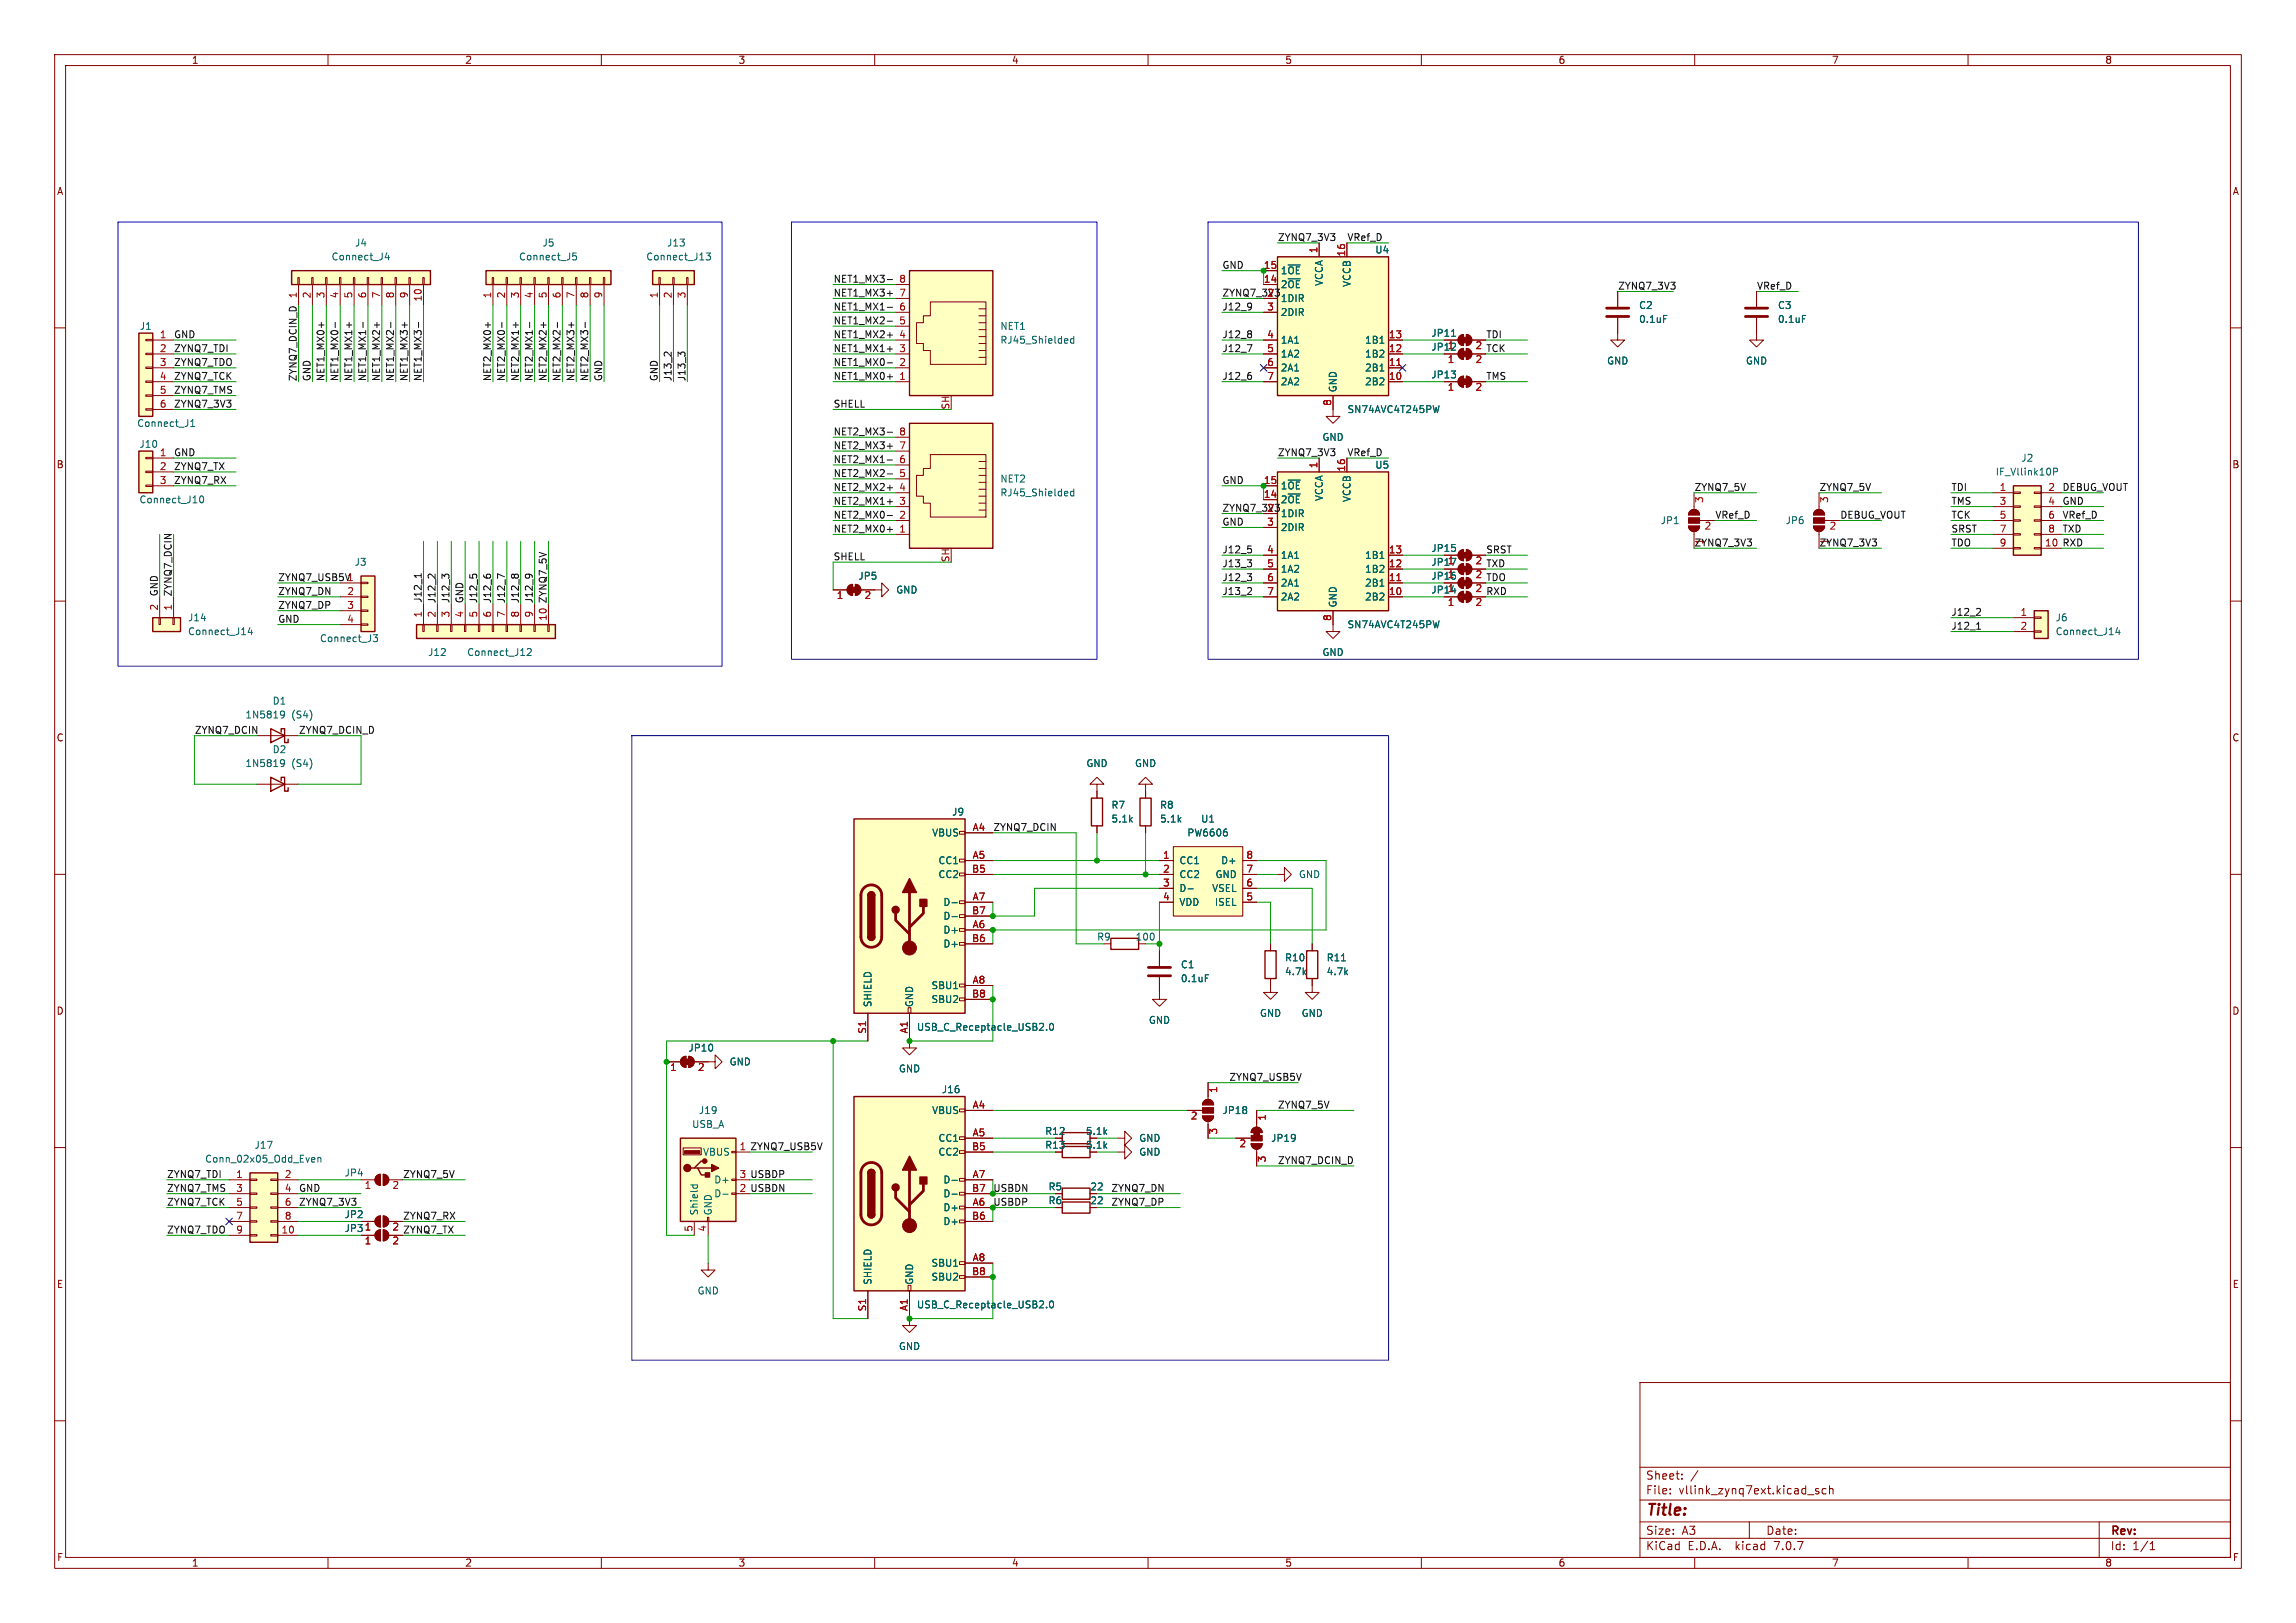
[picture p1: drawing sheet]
<svg xmlns="http://www.w3.org/2000/svg" width="420mm" height="297mm" viewBox="0 0 420 297" stroke-linecap="round" stroke-linejoin="round" font-family="sans-serif">
<defs><g id="words">
<text font-size="2.8" fill="#840000" x="301" y="277.9">Title:</text>
<g font-size="2.1" fill="#840000">
<text x="301" y="273.7">File:</text>
<text x="301" y="271">Sheet:</text>
<text x="307.1" y="273.7">vllink_zynq7ext.kicad_sch</text>
<text x="301" y="281.1">Size:</text>
<text x="307.6" y="281.1">A3</text>
<text x="323" y="281.1">Date:</text>
<text x="386" y="281.3">Rev:</text>
<text x="301" y="283.9">KiCad</text>
<text x="308.7" y="283.9">E.D.A.</text>
<text x="317.6" y="283.9">kicad</text>
<text x="324.8" y="283.9">7.0.7</text>
<text x="386" y="283.9">Id:</text>
<text x="390.1" y="283.9">1/1</text>
</g>
<g font-size="1.8" fill="#840000">
<text x="35" y="11.9">1</text>
<text x="85" y="11.9">2</text>
<text x="135" y="11.9">3</text>
<text x="185" y="11.9">4</text>
<text x="235" y="11.9">5</text>
<text x="285" y="11.9">6</text>
<text x="335" y="11.9">7</text>
<text x="385" y="11.9">8</text>
<text x="10.3" y="35.9">A</text>
<text x="408.3" y="35.9">A</text>
<text x="223.5" y="54.3">ZYNQ7_3V3</text>
<text x="269.8" y="64.2">2 TCK</text>
<text x="10.3" y="85.9">B</text>
<text x="408.2" y="85.9">B</text>
<text x="223.5" y="93.7">ZYNQ7_3V3</text>
<text x="269.8" y="106.1">2 TDO</text>
<text x="269.8" y="103.6">2 TXD</text>
<text x="269.8" y="108.7">2 RXD</text>
<text x="10.3" y="135.9">C</text>
<text x="408.2" y="135.9">C</text>
<text x="10.3" y="185.9">D</text>
<text x="408.2" y="185.9">D</text>
<text x="191.1" y="207.9">R12</text>
<text x="198.5" y="207.9">5.1k</text>
<text x="191.1" y="210.4">R13</text>
<text x="198.5" y="210.4">5.1k</text>
<text x="191.7" y="220.6">R6</text>
<text x="191.7" y="218">R5</text>
<text x="199.3" y="220.6">22</text>
<text x="199.3" y="218">22</text>
<text x="71.7" y="225.5">2 ZYNQ7_TX</text>
<text x="10.3" y="235.9">E</text>
<text x="408.3" y="235.9">E</text>
<text x="10.3" y="285.9">F</text>
<text x="35" y="286.9">1</text>
<text x="85" y="286.9">2</text>
<text x="135" y="286.9">3</text>
<text x="185" y="286.9">4</text>
<text x="235" y="286.9">5</text>
<text x="285" y="286.9">6</text>
<text x="335" y="286.9">7</text>
<text x="385" y="286.9">8</text>
<text x="408.3" y="285.9">F</text>
</g>
<g font-size="1.8" fill="#006464">
<text x="60.6" y="47.9">Connect_J4</text>
<text x="64.8" y="45.3">J4</text>
<text x="94.8" y="47.9">Connect_J5</text>
<text x="99.1" y="45.3">J5</text>
<text x="118.1" y="47.9">Connect_J13</text>
<text x="121.9" y="45.3">J13</text>
<text x="251.5" y="46.6">U4</text>
<text x="234.2" y="52.9">2~{OE}</text>
<text x="234.2" y="50.4">1~{OE}</text>
<text x="242.2" y="52.4" transform="rotate(-90 242.2 52.4)">VCCA</text>
<text x="247.2" y="52.6" transform="rotate(-90 247.2 52.6)">VCCB</text>
<text x="234.2" y="55.5">1DIR</text>
<text x="234.2" y="58">2DIR</text>
<text x="299.7" y="56.7">C2</text>
<text x="299.7" y="59.3">0.1uF</text>
<text x="325.1" y="56.7">C3</text>
<text x="325.1" y="59.3">0.1uF</text>
<text x="25.5" y="60.6">J1</text>
<text x="182.9" y="63.1">RJ45_Shielded</text>
<text x="182.9" y="60.6">NET1</text>
<text x="234.2" y="63.1">1A1</text>
<text x="234.2" y="65.6">1A2</text>
<text x="249.6" y="65.6">1B2</text>
<text x="249.6" y="63.1">1B1</text>
<text x="261.7" y="61.8">JP11</text>
<text x="261.7" y="64.4">JP12</text>
<text x="264.7" y="64.2">1</text>
<text x="234.2" y="68.2">2A1</text>
<text x="234.2" y="70.7">2A2</text>
<text x="244.7" y="71.9" transform="rotate(-90 244.7 71.9)">GND</text>
<text x="249.6" y="70.7">2B2</text>
<text x="249.6" y="68.2">2B1</text>
<text x="261.7" y="69.4">JP13</text>
<text x="293.9" y="66.9">GND</text>
<text x="319.3" y="66.9">GND</text>
<text x="246.4" y="75.8">SN74AVC4T245PW</text>
<text x="25" y="78.3">Connect_J1</text>
<text x="25.4" y="82.1">J10</text>
<text x="241.8" y="80.9">GND</text>
<text x="182.9" y="88.5">NET2</text>
<text x="234.2" y="89.8">1~{OE}</text>
<text x="251.5" y="86">U5</text>
<text x="365" y="87.2">IF_Vllink10P</text>
<text x="369.6" y="84.7">J2</text>
<text x="25.4" y="92.3">Connect_J10</text>
<text x="182.9" y="91">RJ45_Shielded</text>
<text x="234.2" y="92.3">2~{OE}</text>
<text x="234.2" y="94.8">1DIR</text>
<text x="242.2" y="91.8" transform="rotate(-90 242.2 91.8)">VCCA</text>
<text x="247.2" y="92" transform="rotate(-90 247.2 92)">VCCB</text>
<text x="234.2" y="97.4">2DIR</text>
<text x="261.7" y="101.2">JP15</text>
<text x="303.7" y="96.1">JP1</text>
<text x="326.5" y="96.1">JP6</text>
<text x="64.8" y="103.7">J3</text>
<text x="156.9" y="106.3">JP5</text>
<text x="234.2" y="102.5">1A1</text>
<text x="234.2" y="105">1A2</text>
<text x="234.2" y="107.5">2A1</text>
<text x="249.6" y="107.5">2B1</text>
<text x="249.6" y="105">1B2</text>
<text x="249.6" y="102.5">1B1</text>
<text x="261.7" y="103.7">JP17</text>
<text x="261.7" y="106.3">JP16</text>
<text x="264.7" y="106.1">1</text>
<text x="34.3" y="113.9">J14</text>
<text x="163.8" y="108.8">GND</text>
<text x="234.2" y="110.1">2A2</text>
<text x="244.7" y="111.3" transform="rotate(-90 244.7 111.3)">GND</text>
<text x="249.6" y="110.1">2B2</text>
<text x="261.7" y="108.8">JP14</text>
<text x="375.9" y="113.9">J6</text>
<text x="34.3" y="116.4">Connect_J14</text>
<text x="58.4" y="117.7">Connect_J3</text>
<text x="246.4" y="115.2">SN74AVC4T245PW</text>
<text x="375.9" y="116.4">Connect_J14</text>
<text x="78.2" y="120.2">J12</text>
<text x="85.4" y="120.2">Connect_J12</text>
<text x="241.8" y="120.2">GND</text>
<text x="44.8" y="131.7">1N5819</text>
<text x="49.8" y="129.1">D1</text>
<text x="53.3" y="131.7">(S4)</text>
<text x="44.8" y="140.6">1N5819</text>
<text x="49.8" y="138">D2</text>
<text x="53.3" y="140.6">(S4)</text>
<text x="198.6" y="140.6">GND</text>
<text x="207.5" y="140.6">GND</text>
<text x="174.1" y="149.5">J9</text>
<text x="203.2" y="148.2">R7</text>
<text x="212.1" y="148.2">R8</text>
<text x="170.4" y="153.3">VBUS</text>
<text x="203.2" y="150.7">5.1k</text>
<text x="212.1" y="150.7">5.1k</text>
<text x="217.1" y="153.3">PW6606</text>
<text x="219.6" y="150.7">U1</text>
<text x="171.6" y="158.3">CC1</text>
<text x="171.6" y="160.9">CC2</text>
<text x="215.6" y="158.3">CC1</text>
<text x="215.6" y="160.9">CC2</text>
<text x="222.2" y="160.9">GND</text>
<text x="223.3" y="158.3">D+</text>
<text x="237.5" y="160.9">GND</text>
<text x="172.5" y="166">D-</text>
<text x="215.6" y="163.4">D-</text>
<text x="215.6" y="166">VDD</text>
<text x="221.6" y="163.4">VSEL</text>
<text x="222.1" y="166">ISEL</text>
<text x="172.5" y="171">D+</text>
<text x="172.5" y="173.6">D+</text>
<text x="172.5" y="168.5">D-</text>
<text x="200.6" y="172.3">R9</text>
<text x="207.6" y="172.3">100</text>
<text x="215.9" y="177.4">C1</text>
<text x="215.9" y="179.9">0.1uF</text>
<text x="235" y="178.7">4.7k</text>
<text x="235" y="176.1">R10</text>
<text x="242.6" y="178.7">4.7k</text>
<text x="242.6" y="176.1">R11</text>
<text x="159.6" y="184.4" transform="rotate(-90 159.6 184.4)">SHIELD</text>
<text x="167.2" y="184.4" transform="rotate(-90 167.2 184.4)">GND</text>
<text x="170.3" y="181.2">SBU1</text>
<text x="170.3" y="183.7">SBU2</text>
<text x="167.6" y="188.8">USB_C_Receptacle_USB2.0</text>
<text x="210.1" y="187.6">GND</text>
<text x="230.4" y="186.3">GND</text>
<text x="238" y="186.3">GND</text>
<text x="125.8" y="192.6">JP10</text>
<text x="133.4" y="195.2">GND</text>
<text x="164.3" y="196.4">GND</text>
<text x="172.2" y="200.3">J16</text>
<text x="126.5" y="206.6">USB_A</text>
<text x="127.7" y="204.1">J19</text>
<text x="170.4" y="204.1">VBUS</text>
<text x="171.6" y="209.1">CC1</text>
<text x="208.3" y="209.1">GND</text>
<text x="223.5" y="204.1">JP18</text>
<text x="232.4" y="209.1">JP19</text>
<text x="37.4" y="213">Conn_02x05_Odd_Even</text>
<text x="46.5" y="210.4">J17</text>
<text x="62.9" y="215.5">JP4</text>
<text x="128.5" y="211.7">VBUS</text>
<text x="171.6" y="211.7">CC2</text>
<text x="208.3" y="211.7">GND</text>
<text x="130.6" y="219.3">D-</text>
<text x="130.6" y="216.8">D+</text>
<text x="172.5" y="221.8">D+</text>
<text x="172.5" y="216.8">D-</text>
<text x="172.5" y="219.3">D-</text>
<text x="62.9" y="225.7">JP3</text>
<text x="62.9" y="223.1">JP2</text>
<text x="66.6" y="225.5">1</text>
<text x="127.9" y="222.5" transform="rotate(-90 127.9 222.5)">Shield</text>
<text x="130.4" y="222.5" transform="rotate(-90 130.4 222.5)">GND</text>
<text x="172.5" y="224.4">D+</text>
<text x="170.3" y="232">SBU1</text>
<text x="127.5" y="237.1">GND</text>
<text x="159.6" y="235.2" transform="rotate(-90 159.6 235.2)">SHIELD</text>
<text x="167.2" y="235.2" transform="rotate(-90 167.2 235.2)">GND</text>
<text x="167.6" y="239.6">USB_C_Receptacle_USB2.0</text>
<text x="170.3" y="234.5">SBU2</text>
<text x="164.3" y="247.2">GND</text>
</g>
<g font-size="1.8" fill="#0f0f0f">
<text x="233.7" y="44.2">ZYNQ7_3V3</text>
<text x="246.4" y="44.2">VRef_D</text>
<text x="152.4" y="51.8">NET1_MX3-</text>
<text x="223.5" y="49.3">GND</text>
<text x="295.9" y="53.1">ZYNQ7_3V3</text>
<text x="321.3" y="53.1">VRef_D</text>
<text x="152.4" y="54.3">NET1_MX3+</text>
<text x="152.4" y="56.9">NET1_MX1-</text>
<text x="152.4" y="59.4">NET1_MX2-</text>
<text x="223.5" y="56.9">J12_9</text>
<text x="31.7" y="64.5">ZYNQ7_TDI</text>
<text x="31.7" y="62">GND</text>
<text x="152.4" y="64.5">NET1_MX1+</text>
<text x="152.4" y="62">NET1_MX2+</text>
<text x="223.5" y="64.5">J12_7</text>
<text x="223.5" y="62">J12_8</text>
<text x="271.8" y="62">TDI</text>
<text x="31.7" y="67">ZYNQ7_TDO</text>
<text x="31.7" y="69.6">ZYNQ7_TCK</text>
<text x="54.3" y="69.8" transform="rotate(-90 54.3 69.8)">ZYNQ7_DCIN_D</text>
<text x="56.9" y="69.8" transform="rotate(-90 56.9 69.8)">GND</text>
<text x="59.4" y="69.8" transform="rotate(-90 59.4 69.8)">NET1_MX0+</text>
<text x="62" y="69.8" transform="rotate(-90 62 69.8)">NET1_MX0-</text>
<text x="64.5" y="69.8" transform="rotate(-90 64.5 69.8)">NET1_MX1+</text>
<text x="67" y="69.8" transform="rotate(-90 67 69.8)">NET1_MX1-</text>
<text x="69.6" y="69.8" transform="rotate(-90 69.6 69.8)">NET1_MX2+</text>
<text x="72.1" y="69.8" transform="rotate(-90 72.1 69.8)">NET1_MX2-</text>
<text x="74.7" y="69.8" transform="rotate(-90 74.7 69.8)">NET1_MX3+</text>
<text x="77.2" y="69.8" transform="rotate(-90 77.2 69.8)">NET1_MX3-</text>
<text x="89.9" y="69.8" transform="rotate(-90 89.9 69.8)">NET2_MX0+</text>
<text x="92.4" y="69.8" transform="rotate(-90 92.4 69.8)">NET2_MX0-</text>
<text x="95" y="69.8" transform="rotate(-90 95 69.8)">NET2_MX1+</text>
<text x="97.5" y="69.8" transform="rotate(-90 97.5 69.8)">NET2_MX1-</text>
<text x="100.1" y="69.8" transform="rotate(-90 100.1 69.8)">NET2_MX2+</text>
<text x="102.6" y="69.8" transform="rotate(-90 102.6 69.8)">NET2_MX2-</text>
<text x="105.1" y="69.8" transform="rotate(-90 105.1 69.8)">NET2_MX3+</text>
<text x="107.7" y="69.8" transform="rotate(-90 107.7 69.8)">NET2_MX3-</text>
<text x="110.2" y="69.8" transform="rotate(-90 110.2 69.8)">GND</text>
<text x="120.4" y="69.8" transform="rotate(-90 120.4 69.8)">GND</text>
<text x="122.9" y="69.8" transform="rotate(-90 122.9 69.8)">J13_2</text>
<text x="125.5" y="69.8" transform="rotate(-90 125.5 69.8)">J13_3</text>
<text x="152.4" y="69.6">NET1_MX0+</text>
<text x="152.4" y="67">NET1_MX0-</text>
<text x="223.5" y="69.6">J12_6</text>
<text x="271.8" y="69.6">TMS</text>
<text x="31.7" y="74.7">ZYNQ7_3V3</text>
<text x="31.7" y="72.1">ZYNQ7_TMS</text>
<text x="152.4" y="74.7">SHELL</text>
<text x="31.7" y="83.6">GND</text>
<text x="152.4" y="79.7">NET2_MX3-</text>
<text x="152.4" y="82.3">NET2_MX3+</text>
<text x="233.7" y="83.6">ZYNQ7_3V3</text>
<text x="246.4" y="83.6">VRef_D</text>
<text x="31.7" y="86.1">ZYNQ7_TX</text>
<text x="31.7" y="88.6">ZYNQ7_RX</text>
<text x="152.4" y="89.9">NET2_MX2+</text>
<text x="152.4" y="87.4">NET2_MX2-</text>
<text x="152.4" y="84.8">NET2_MX1-</text>
<text x="223.5" y="88.6">GND</text>
<text x="309.9" y="89.9">ZYNQ7_5V</text>
<text x="332.7" y="89.9">ZYNQ7_5V</text>
<text x="356.9" y="89.9">TDI</text>
<text x="377.2" y="89.9">DEBUG_VOUT</text>
<text x="152.4" y="92.4">NET2_MX1+</text>
<text x="152.4" y="95">NET2_MX0-</text>
<text x="313.7" y="95">VRef_D</text>
<text x="336.5" y="95">DEBUG_VOUT</text>
<text x="356.9" y="95">TCK</text>
<text x="356.9" y="92.4">TMS</text>
<text x="377.2" y="92.4">GND</text>
<text x="377.2" y="95">VRef_D</text>
<text x="152.4" y="97.5">NET2_MX0+</text>
<text x="223.5" y="101.3">J12_5</text>
<text x="223.5" y="96.3">GND</text>
<text x="271.8" y="101.3">SRST</text>
<text x="309.9" y="100.1">ZYNQ7_3V3</text>
<text x="311.9" y="99.8" transform="rotate(-90 311.9 99.8)">1</text>
<text x="332.7" y="100.1">ZYNQ7_3V3</text>
<text x="334.7" y="99.8" transform="rotate(-90 334.7 99.8)">1</text>
<text x="356.9" y="100.1">TDO</text>
<text x="356.9" y="97.5">SRST</text>
<text x="377.2" y="100.1">RXD</text>
<text x="377.2" y="97.5">TXD</text>
<text x="50.8" y="106.4">ZYNQ7_USB5V1</text>
<text x="152.4" y="102.6">SHELL</text>
<text x="223.5" y="106.4">J12_3</text>
<text x="223.5" y="103.9">J13_3</text>
<text x="28.9" y="109.2" transform="rotate(-90 28.9 109.2)">GND</text>
<text x="31.5" y="109.2" transform="rotate(-90 31.5 109.2)">ZYNQ7_DCIN</text>
<text x="50.8" y="109">ZYNQ7_DN</text>
<text x="50.8" y="111.5">ZYNQ7_DP</text>
<text x="77.2" y="110.4" transform="rotate(-90 77.2 110.4)">J12_1</text>
<text x="79.7" y="110.5" transform="rotate(-90 79.7 110.5)">J12_2</text>
<text x="82.3" y="110.5" transform="rotate(-90 82.3 110.5)">J12_3</text>
<text x="84.8" y="110.5" transform="rotate(-90 84.8 110.5)">GND</text>
<text x="87.4" y="110.5" transform="rotate(-90 87.4 110.5)">J12_5</text>
<text x="89.9" y="110.5" transform="rotate(-90 89.9 110.5)">J12_6</text>
<text x="92.4" y="110.5" transform="rotate(-90 92.4 110.5)">J12_7</text>
<text x="95" y="110.5" transform="rotate(-90 95 110.5)">J12_8</text>
<text x="97.5" y="110.5" transform="rotate(-90 97.5 110.5)">J12_9</text>
<text x="100.1" y="110.5" transform="rotate(-90 100.1 110.5)">ZYNQ7_5V</text>
<text x="223.5" y="109">J13_2</text>
<text x="356.9" y="112.8">J12_2</text>
<text x="50.8" y="114">GND</text>
<text x="356.9" y="115.3">J12_1</text>
<text x="35.6" y="134.4">ZYNQ7_DCIN</text>
<text x="54.6" y="134.4">ZYNQ7_DCIN_D</text>
<text x="181.6" y="152.1">ZYNQ7_DCIN</text>
<text x="224.8" y="197.9">ZYNQ7_USB5V</text>
<text x="233.7" y="202.9">ZYNQ7_5V</text>
<text x="30.5" y="215.6">ZYNQ7_TDI</text>
<text x="73.7" y="215.6">ZYNQ7_5V</text>
<text x="135.2" y="210.6">1 ZYNQ7_USB5V</text>
<text x="135.2" y="215.6">3 USBDP</text>
<text x="233.7" y="213.1">ZYNQ7_DCIN_D</text>
<text x="30.5" y="218.2">ZYNQ7_TMS</text>
<text x="30.5" y="220.7">ZYNQ7_TCK</text>
<text x="54.6" y="218.2">GND</text>
<text x="54.6" y="220.7">ZYNQ7_3V3</text>
<text x="135.2" y="218.2">2 USBDN</text>
<text x="181.6" y="218.2">USBDN</text>
<text x="181.6" y="220.7">USBDP</text>
<text x="203.2" y="218.2">ZYNQ7_DN</text>
<text x="203.2" y="220.7">ZYNQ7_DP</text>
<text x="30.5" y="225.8">ZYNQ7_TDO</text>
<text x="73.7" y="223.3">ZYNQ7_RX</text>
</g>
<g font-size="1.8" fill="#a90000">
<text x="241" y="46.4" transform="rotate(-90 241 46.4)">1</text>
<text x="246.1" y="47" transform="rotate(-90 246.1 47)">16</text>
<text x="164.4" y="51.8">8</text>
<text x="231.1" y="51.8">14</text>
<text x="231.1" y="49.3">15</text>
<text x="54.4" y="54.7" transform="rotate(-90 54.4 54.7)">1</text>
<text x="56.9" y="54.7" transform="rotate(-90 56.9 54.7)">2</text>
<text x="59.4" y="54.7" transform="rotate(-90 59.4 54.7)">3</text>
<text x="62" y="54.7" transform="rotate(-90 62 54.7)">4</text>
<text x="64.5" y="54.7" transform="rotate(-90 64.5 54.7)">5</text>
<text x="67.1" y="54.7" transform="rotate(-90 67.1 54.7)">6</text>
<text x="69.6" y="54.7" transform="rotate(-90 69.6 54.7)">7</text>
<text x="72.1" y="54.7" transform="rotate(-90 72.1 54.7)">8</text>
<text x="74.7" y="54.7" transform="rotate(-90 74.7 54.7)">9</text>
<text x="77.2" y="55.3" transform="rotate(-90 77.2 55.3)">10</text>
<text x="89.9" y="54.7" transform="rotate(-90 89.9 54.7)">1</text>
<text x="92.5" y="54.7" transform="rotate(-90 92.5 54.7)">2</text>
<text x="95" y="54.7" transform="rotate(-90 95 54.7)">3</text>
<text x="97.5" y="54.7" transform="rotate(-90 97.5 54.7)">4</text>
<text x="100.1" y="54.7" transform="rotate(-90 100.1 54.7)">5</text>
<text x="102.6" y="54.7" transform="rotate(-90 102.6 54.7)">6</text>
<text x="105.2" y="54.7" transform="rotate(-90 105.2 54.7)">7</text>
<text x="107.7" y="54.7" transform="rotate(-90 107.7 54.7)">8</text>
<text x="110.2" y="54.7" transform="rotate(-90 110.2 54.7)">9</text>
<text x="120.4" y="54.7" transform="rotate(-90 120.4 54.7)">1</text>
<text x="122.9" y="54.7" transform="rotate(-90 122.9 54.7)">2</text>
<text x="125.5" y="54.7" transform="rotate(-90 125.5 54.7)">3</text>
<text x="164.4" y="59.4">5</text>
<text x="164.4" y="56.9">6</text>
<text x="164.4" y="54.4">7</text>
<text x="231.7" y="54.4">2</text>
<text x="231.7" y="56.9">3</text>
<text x="29.1" y="62">1</text>
<text x="29.1" y="64.5">2</text>
<text x="164.4" y="64.5">3</text>
<text x="164.4" y="62">4</text>
<text x="231.7" y="62">4</text>
<text x="231.7" y="64.5">5</text>
<text x="254" y="64.5">12</text>
<text x="254" y="62">13</text>
<text x="269.8" y="64.2">2</text>
<text x="29.1" y="67.1">3</text>
<text x="29.1" y="69.6">4</text>
<text x="164.4" y="69.6">1</text>
<text x="164.4" y="67.1">2</text>
<text x="231.7" y="67.1">6</text>
<text x="231.7" y="69.6">7</text>
<text x="254" y="69.6">10</text>
<text x="254" y="67.1">11</text>
<text x="264.7" y="66.8">1</text>
<text x="264.7" y="71.8">1</text>
<text x="269.8" y="66.8">2</text>
<text x="269.8" y="71.8">2</text>
<text x="29.1" y="72.1">5</text>
<text x="29.1" y="74.7">6</text>
<text x="173.7" y="75" transform="rotate(-90 173.7 75)">SH</text>
<text x="243.6" y="74.4" transform="rotate(-90 243.6 74.4)">8</text>
<text x="29.1" y="83.6">1</text>
<text x="164.4" y="82.3">7</text>
<text x="164.4" y="79.8">8</text>
<text x="29.1" y="86.1">2</text>
<text x="29.1" y="88.6">3</text>
<text x="164.4" y="89.9">4</text>
<text x="164.4" y="87.4">5</text>
<text x="164.4" y="84.8">6</text>
<text x="231.1" y="88.6">15</text>
<text x="241" y="85.8" transform="rotate(-90 241 85.8)">1</text>
<text x="246.1" y="86.4" transform="rotate(-90 246.1 86.4)">16</text>
<text x="365.7" y="89.9">1</text>
<text x="374.6" y="89.9">2</text>
<text x="164.4" y="95">2</text>
<text x="164.4" y="92.5">3</text>
<text x="231.1" y="91.2">14</text>
<text x="231.7" y="93.7">2</text>
<text x="311.9" y="92.1" transform="rotate(-90 311.9 92.1)">3</text>
<text x="334.7" y="92.1" transform="rotate(-90 334.7 92.1)">3</text>
<text x="365.7" y="92.5">3</text>
<text x="365.7" y="95">5</text>
<text x="374.6" y="92.5">4</text>
<text x="374.6" y="95">6</text>
<text x="164.4" y="97.5">1</text>
<text x="231.7" y="96.3">3</text>
<text x="231.7" y="101.3">4</text>
<text x="254" y="101.3">13</text>
<text x="311.7" y="97.2">2</text>
<text x="334.6" y="97.2">2</text>
<text x="365.7" y="97.5">7</text>
<text x="365.7" y="100.1">9</text>
<text x="374" y="100.1">10</text>
<text x="374.6" y="97.5">8</text>
<text x="173.7" y="103" transform="rotate(-90 173.7 103)">SH</text>
<text x="231.7" y="103.9">5</text>
<text x="231.7" y="106.4">6</text>
<text x="254" y="106.4">11</text>
<text x="254" y="103.9">12</text>
<text x="264.7" y="103.6">1</text>
<text x="269.8" y="106.1">2</text>
<text x="269.8" y="103.6">2</text>
<text x="29" y="111.8" transform="rotate(-90 29 111.8)">2</text>
<text x="31.5" y="111.8" transform="rotate(-90 31.5 111.8)">1</text>
<text x="63.4" y="109">2</text>
<text x="63.4" y="111.5">3</text>
<text x="77.2" y="113.1" transform="rotate(-90 77.2 113.1)">1</text>
<text x="79.8" y="113.1" transform="rotate(-90 79.8 113.1)">2</text>
<text x="82.3" y="113.1" transform="rotate(-90 82.3 113.1)">3</text>
<text x="84.8" y="113.1" transform="rotate(-90 84.8 113.1)">4</text>
<text x="87.4" y="113.1" transform="rotate(-90 87.4 113.1)">5</text>
<text x="89.9" y="113.1" transform="rotate(-90 89.9 113.1)">6</text>
<text x="92.5" y="113.1" transform="rotate(-90 92.5 113.1)">7</text>
<text x="95" y="113.1" transform="rotate(-90 95 113.1)">8</text>
<text x="97.5" y="113.1" transform="rotate(-90 97.5 113.1)">9</text>
<text x="100.1" y="113.7" transform="rotate(-90 100.1 113.7)">10</text>
<text x="153" y="109.9">1</text>
<text x="158" y="109.9">2</text>
<text x="231.7" y="109">7</text>
<text x="243.6" y="113.7" transform="rotate(-90 243.6 113.7)">8</text>
<text x="254" y="109">10</text>
<text x="264.7" y="111.2">1</text>
<text x="264.7" y="108.7">1</text>
<text x="269.8" y="111.2">2</text>
<text x="269.8" y="108.7">2</text>
<text x="369.5" y="112.8">1</text>
<text x="63.4" y="114">4</text>
<text x="369.5" y="115.3">2</text>
<text x="177.8" y="152.1">A4</text>
<text x="177.7" y="159.8">B5</text>
<text x="177.8" y="157.2">A5</text>
<text x="212.7" y="157.2">1</text>
<text x="212.7" y="159.8">2</text>
<text x="227.9" y="159.8">7</text>
<text x="227.9" y="157.2">8</text>
<text x="177.7" y="167.4">B7</text>
<text x="177.8" y="164.8">A7</text>
<text x="212.7" y="162.3">3</text>
<text x="212.7" y="164.8">4</text>
<text x="227.9" y="164.8">5</text>
<text x="227.9" y="162.3">6</text>
<text x="177.7" y="172.5">B6</text>
<text x="177.8" y="169.9">A6</text>
<text x="177.7" y="182.6">B8</text>
<text x="177.8" y="180.1">A8</text>
<text x="158.5" y="189.3" transform="rotate(-90 158.5 189.3)">S1</text>
<text x="166.1" y="189.2" transform="rotate(-90 166.1 189.2)">A1</text>
<text x="122.5" y="196.3">1</text>
<text x="127.6" y="196.3">2</text>
<text x="177.8" y="202.9">A4</text>
<text x="223" y="200.1" transform="rotate(-90 223 200.1)">1</text>
<text x="177.8" y="208">A5</text>
<text x="217.7" y="205.2">2</text>
<text x="223" y="207.7" transform="rotate(-90 223 207.7)">3</text>
<text x="231.9" y="205.2" transform="rotate(-90 231.9 205.2)">1</text>
<text x="43.1" y="215.6">1</text>
<text x="52" y="215.6">2</text>
<text x="177.7" y="210.6">B5</text>
<text x="177.8" y="215.6">A7</text>
<text x="226.6" y="210.3">2</text>
<text x="231.9" y="212.8" transform="rotate(-90 231.9 212.8)">3</text>
<text x="43.1" y="218.2">3</text>
<text x="43.1" y="220.7">5</text>
<text x="52" y="218.2">4</text>
<text x="52" y="220.7">6</text>
<text x="66.6" y="217.9">1</text>
<text x="71.7" y="217.9">2</text>
<text x="177.7" y="218.2">B7</text>
<text x="177.8" y="220.7">A6</text>
<text x="43.1" y="223.3">7</text>
<text x="43.1" y="225.8">9</text>
<text x="51.4" y="225.8">10</text>
<text x="52" y="223.3">8</text>
<text x="71.7" y="225.5">2</text>
<text x="126.7" y="225.5" transform="rotate(-90 126.7 225.5)">5</text>
<text x="129.3" y="225.5" transform="rotate(-90 129.3 225.5)">4</text>
<text x="177.7" y="223.3">B6</text>
<text x="66.6" y="228">1</text>
<text x="71.7" y="228">2</text>
<text x="177.7" y="233.4">B8</text>
<text x="177.8" y="230.9">A8</text>
<text x="158.5" y="240.1" transform="rotate(-90 158.5 240.1)">S1</text>
<text x="166.1" y="240" transform="rotate(-90 166.1 240)">A1</text>
</g>
</g></defs>
<g fill="none" stroke="#840000" stroke-width=".18">
<path d="M10 10h400v277h-400zM12 12h396v273h-396zM60 10v2M110 10v2M160 10v2M210 10v2M260 10v2M310 10v2M360 10v2M10 60h2M54.5 50.8h.2v1.3h-.2zM54.6 52.1v3.8"/>
<path d="M57 50.8h.3v1.3h-.3zM57.1 52.1v3.8M59.6 50.8h.2v1.3h-.2zM59.7 52.1v3.8M62.1 50.8h.3v1.3h-.3zM62.2 52.1v3.8M64.6 50.8h.3v1.3h-.3zM64.8 52.1v3.8M67.2 50.8h.2v1.3h-.2zM67.3 52.1v3.8M69.7 50.8h.3v1.3h-.3zM69.8 52.1v3.8"/>
<path d="M72.3 50.8h.2v1.3h-.2zM72.4 52.1v3.8M74.8 50.8h.3v1.3h-.3zM74.9 52.1v3.8M77.3 50.8h.3v1.3h-.3zM77.5 52.1v3.8M90 50.8h.3v1.3h-.3zM90.2 52.1v3.8M92.6 50.8h.2v1.3h-.2zM92.7 52.1v3.8M95.1 50.8h.3v1.3h-.3zM95.2 52.1v3.8"/>
<path d="M97.7 50.8h.2v1.3h-.2zM97.8 52.1v3.8M100.2 50.8h.3v1.3h-.3zM100.3 52.1v3.8M102.7 50.8h.3v1.3h-.3zM102.9 52.1v3.8M105.3 50.8h.2v1.3h-.2zM105.4 52.1v3.8M107.8 50.8h.3v1.3h-.3zM107.9 52.1v3.8M110.4 50.8h.2v1.3h-.2zM110.5 52.1v3.8"/>
<path d="M120.5 50.8h.3v1.3h-.3zM120.6 52.1v3.8M123.1 50.8h.2v1.3h-.2zM123.2 52.1v3.8M125.6 50.8h.3v1.3h-.3zM125.7 52.1v3.8M163.8 52.1h2.6M163.8 57.2h2.6M163.8 59.7h2.6M163.8 54.6h2.6M170.2 55.2h10.1v11.5h-10.1v-2.6h-1.3v-1.2h-1.3v-3.8h1.3v-1.3h1.3zM179.1 59.1h1.2"/>
<path d="M179.1 57.8h1.2M179.1 56.5h1.2M231.1 52.1h2.6M231.1 49.5h2.6M231.1 57.2h2.6M241.3 44.5v2.5M246.4 44.5v2.5M295.9 58.2v4h1.3l-1.3 1.3-1.3-1.3h1.3M295.9 53.3v2.8M321.3 58.2v4h1.3l-1.3 1.3-1.3-1.3h1.3M321.3 53.3v2.8M408 60h2"/>
<path d="M26.7 74.8h1.2v.3h-1.2zM26.7 72.3h1.2v.2h-1.2zM26.7 69.7h1.2v.3h-1.2zM26.7 67.2h1.2v.2h-1.2zM26.7 64.6h1.2v.3h-1.2zM26.7 62.1h1.2v.3h-1.2zM27.9 62.2h3.8M27.9 64.8h3.8M27.9 69.9h3.8M27.9 67.3h3.8M27.9 72.4h3.8M27.9 74.9h3.8"/>
<path d="M163.8 62.2h2.6M163.8 64.8h2.6M163.8 69.9h2.6M163.8 67.3h2.6M179.1 65.4h1.2M179.1 64.1h1.2M179.1 62.9h1.2M179.1 61.6h1.2M179.1 60.3h1.2M231.1 62.2h2.6M231.1 64.8h2.6M231.1 69.9h2.6"/>
<path d="M231.1 67.3h2.6M243.8 72.4v3.8h1.3l-1.3 1.3-1.2-1.3h1.2M254 62.2h2.5M254 64.8h2.5M254 69.9h2.5M254 67.3h2.5M264.2 62.2h2.5M264.2 64.8h2.5M264.2 69.9h2.5M267 61.5l.7-.3v2a1.02 1.02 0 0 1-.9-.6 1.02 1.02 0 0 1 .2-1.1zM267 64l.7-.2v2a1.02 1.02 0 0 1-.9-.7 1.02 1.02 0 0 1 .2-1.1zM267 69.1l.7-.3v2.1a1.02 1.02 0 0 1-.9-.7 1.02 1.02 0 0 1 .2-1.1z"/>
<path d="M268.2 61.2a1.02 1.02 0 0 1 1 1 1.02 1.02 0 0 1-1 1zM268.2 63.8a1.02 1.02 0 0 1 1 1 1.02 1.02 0 0 1-1 1zM268.2 68.8a1.02 1.02 0 0 1 1 1.1 1.02 1.02 0 0 1-1 1zM269.2 62.2h2.6M269.2 69.9h2.6M26.7 88.8h1.2v.2h-1.2zM26.7 86.2h1.2v.3h-1.2zM26.7 83.7h1.2v.2h-1.2zM27.9 83.8h3.8M27.9 86.4h3.8M27.9 88.9h3.8M163.8 95.3h2.6"/>
<path d="M163.8 90.2h2.6M163.8 92.7h2.6M163.8 97.8h2.6M163.8 87.6h2.6M163.8 85.1h2.6M163.8 82.6h2.6M163.8 80h2.6M170.2 83.2h10.1v11.4h-10.1v-2.5h-1.3v-1.3h-1.3v-3.8h1.3v-1.3h1.3zM179.1 93.3h1.2M179.1 92.1h1.2M179.1 90.8h1.2M179.1 89.5h1.2"/>
<path d="M179.1 88.3h1.2M179.1 87h1.2M179.1 85.7h1.2M179.1 84.5h1.2M231.1 88.9h2.6M231.1 91.4h2.6M231.1 96.5h2.6M241.3 83.8v2.6M246.4 83.8v2.6M308.9 96.3h2a1.02 1.02 0 0 1-1 1 1.02 1.02 0 0 1-1-1zM309.2 93.5a1.01 1.01 0 0 1 1.1-.2 1.01 1.01 0 0 1 .6 .9h-2zM309.9 90.2v3"/>
<path d="M309.9 97.3v3M310.9 95.3h2.8M331.7 96.3h2.1a1.02 1.02 0 0 1-1.1 1 1.02 1.02 0 0 1-1-1zM332 93.5a1.01 1.01 0 0 1 1.1-.2 1.01 1.01 0 0 1 .7 .9h-2.1zM332.7 90.2v3M332.7 97.3v3M333.8 95.3h2.7M364.5 95.3h3.8M364.5 90.2h3.8M364.5 92.7h3.8M364.5 97.8h3.8M368.3 97.7h1.3v.2h-1.3z"/>
<path d="M368.3 95.1h1.3v.3h-1.3zM368.3 92.6h1.3v.2h-1.3zM368.3 90h1.3v.3h-1.3zM372.1 97.7h1.3v.2h-1.3zM372.1 95.1h1.3v.3h-1.3zM372.1 92.6h1.3v.2h-1.3zM372.1 90h1.3v.3h-1.3zM373.4 95.3h3.8M373.4 90.2h3.8M373.4 92.7h3.8M373.4 97.8h3.8M10 110h2"/>
<path d="M29.1 113h.2v1.3h-.2zM29.2 109.2v3.8M31.6 113h.3v1.3h-.3zM31.7 109.2v3.8M62.2 109.2h3.8M62.2 106.7h3.8M62.2 111.8h3.8M62.2 114.3h3.8M66 114.2h1.3v.2h-1.3zM66 111.6h1.3v.3h-1.3zM66 109.1h1.3v.2h-1.3zM66 106.6h1.3v.2h-1.3z"/>
<path d="M77.3 114.3h.3v1.3h-.3zM77.5 110.5v3.8M79.9 114.3h.2v1.3h-.2zM80 110.5v3.8M82.4 114.3h.3v1.3h-.3zM82.5 110.5v3.8M85 114.3h.2v1.3h-.2zM85.1 110.5v3.8M87.5 114.3h.3v1.3h-.3zM87.6 110.5v3.8M90 114.3h.3v1.3h-.3zM90.2 110.5v3.8"/>
<path d="M92.6 114.3h.2v1.3h-.2zM92.7 110.5v3.8M95.1 114.3h.3v1.3h-.3zM95.2 110.5v3.8M97.7 114.3h.2v1.3h-.2zM97.8 110.5v3.8M100.2 114.3h.3v1.3h-.3zM100.3 110.5v3.8M152.4 108h2.5M155.3 107.2l.7-.3v2.1a1.02 1.02 0 0 1-1-.7 1.02 1.02 0 0 1 .3-1.1zM156.5 106.9a1.02 1.02 0 0 1 1 1.1 1.02 1.02 0 0 1-1 1zM157.5 108h3.8v-1.3l1.3 1.3-1.3 1.2v-1.2"/>
<path d="M231.1 104.1h2.6M231.1 109.2h2.6M231.1 106.7h2.6M231.1 101.6h2.6M243.8 111.8v3.8h1.3l-1.3 1.2-1.2-1.2h1.2M254 104.1h2.5M254 109.2h2.5M254 106.7h2.5M254 101.6h2.5M264.2 104.1h2.5M264.2 109.2h2.5M264.2 106.7h2.5"/>
<path d="M264.2 101.6h2.5M267 103.4l.7-.3v2.1a1.02 1.02 0 0 1-.9-.7 1.02 1.02 0 0 1 .2-1.1zM267 108.5l.7-.3v2a1.02 1.02 0 0 1-.9-.6 1.02 1.02 0 0 1 .2-1.1zM267 105.9l.7-.2v2a1.02 1.02 0 0 1-.9-.7 1.02 1.02 0 0 1 .2-1.1zM267 100.9l.7-.3v2a1.02 1.02 0 0 1-.9-.6 1.02 1.02 0 0 1 .2-1.1zM268.2 103.1a1.02 1.02 0 0 1 1 1 1.02 1.02 0 0 1-1 1.1zM268.2 108.2a1.02 1.02 0 0 1 1 1 1.02 1.02 0 0 1-1 1zM268.2 105.7a1.02 1.02 0 0 1 1 1 1.02 1.02 0 0 1-1 1zM268.2 100.6a1.02 1.02 0 0 1 1 1 1.02 1.02 0 0 1-1 1zM269.2 101.6h2.6M364.5 100.3h3.8M368.3 100.2h1.3v.3h-1.3z"/>
<path d="M368.3 113h3.8M368.3 115.6h3.8M372.1 115.4h1.3v.3h-1.3zM372.1 112.9h1.3v.3h-1.3zM372.1 100.2h1.3v.3h-1.3zM373.4 100.3h3.8M408 110h2M47 134.6h7.6M10 160h2M47 143.5h7.6M175.5 159.8h1v.5h-1zM175.5 157.2h1v.5h-1z"/>
<path d="M175.5 152.1h1v.6h-1zM176.5 157.5h5.1M176.5 152.4h5.1M200.7 143.5h1.2l-1.2-1.3-1.3 1.3h1.3v2.6M200.7 151.1v1.3M209.5 143.5h1.3l-1.3-1.3-1.2 1.3h1.2v2.6M209.5 151.1v1.3M212.1 157.5h2.5M214.6 154.9h12.7v12.7h-12.7zM227.3 157.5h2.6M408 160h2M175.5 172.5h1v.5h-1z"/>
<path d="M175.5 169.9h1v.5h-1zM175.5 167.4h1v.5h-1zM175.5 164.8h1v.6h-1zM176.5 160h5.1M176.5 165.1h5.1M176.5 170.2h5.1M176.5 172.7h5.1M176.5 167.6h5.1M212.1 178.8v4.1h1.3l-1.3 1.3-1.3-1.3h1.3M212.1 160h2.5M212.1 162.6h2.5M212.1 165.1h2.5"/>
<path d="M212.1 174v2.8M227.3 160h2.6M227.3 162.6h2.6M227.3 165.1h2.6M232.4 179.1v2.5h1.3l-1.3 1.3-1.3-1.3h1.3M232.4 172.7v1.3M233.7 160h1.2v-1.2l1.3 1.2-1.3 1.3v-1.3M240 179.1v2.5h1.3l-1.3 1.3-1.2-1.3h1.2M240 172.7v1.3M121.9 194.3h2.6M124.8 193.6l.7-.3v2a1.02 1.02 0 0 1-1-.6 1.02 1.02 0 0 1 .3-1.1zM126 193.3a1.02 1.02 0 0 1 1 1 1.02 1.02 0 0 1-1 1z"/>
<path d="M127 194.3h3.8v-1.3l1.3 1.3-1.3 1.3v-1.3M158.7 185.4v5.1M166.1 184.4h.5v1h-.5zM166.4 185.4v6.4h1.2l-1.2 1.2-1.3-1.2h1.3M175.5 182.6h1v.5h-1zM175.5 180.1h1v.5h-1zM176.5 180.3h5.1M176.5 182.9h5.1M221 198.1v3.1M10 210h2M41.9 215.9h3.8M41.9 218.4h3.8"/>
<path d="M45.7 218.3h1.3v.3h-1.3zM45.7 215.8h1.3v.2h-1.3zM49.5 218.3h1.3v.3h-1.3zM49.5 215.8h1.3v.2h-1.3zM50.8 215.9h3.8M50.8 218.4h3.8M66 215.9h2.6M68.9 215.2l.7-.3v2a1.02 1.02 0 0 1-.9-.6 1.02 1.02 0 0 1 .2-1.1zM70.1 214.9a1.02 1.02 0 0 1 1 1 1.02 1.02 0 0 1-1 1zM71.1 215.9h2.6M125 210.1h3.3v1.2h-3.3zM133.9 218.3h.7v.3h-.7z"/>
<path d="M133.9 215.8h.7v.2h-.7zM133.9 210.7h.7v.2h-.7zM134.6 215.9h2.6M134.6 210.8h2.6M175.5 218.2h1v.5h-1zM175.5 215.6h1v.6h-1zM175.5 210.6h1v.5h-1zM175.5 208h1v.5h-1zM175.5 202.9h1v.6h-1zM176.5 215.9h5.1M176.5 218.4h5.1M176.5 203.2h5.1"/>
<path d="M176.5 210.8h5.1M176.5 208.3h5.1M204.5 208.3h1.2v-1.3l1.3 1.3-1.3 1.3v-1.3M204.5 210.8h1.2v-1.2l1.3 1.2-1.3 1.3v-1.3M217.2 203.2h2.8M220 204.2h2a1.02 1.02 0 0 1-1 1 1.02 1.02 0 0 1-1-1zM220.3 201.5a1.02 1.02 0 0 1 1.1-.2 1.02 1.02 0 0 1 .6 .9h-2zM221 205.2v3.1M226.1 208.3h2.8M228.9 209.3h2a1.02 1.02 0 0 1-1 1 1.02 1.02 0 0 1-1-1zM229.2 206.5a1.02 1.02 0 0 1 1.1-.2 1.02 1.02 0 0 1 .6 1h-2zM229.9 203.2v3"/>
<path d="M229.9 210.3v3.1M408 210h2M41.9 226.1h3.8M41.9 221h3.8M41.9 223.5h3.8M45.7 225.9h1.3v.3h-1.3zM45.7 223.4h1.3v.2h-1.3zM45.7 220.9h1.3v.2h-1.3zM49.5 225.9h1.3v.3h-1.3zM49.5 223.4h1.3v.2h-1.3zM49.5 220.9h1.3v.2h-1.3zM50.8 226.1h3.8"/>
<path d="M50.8 221h3.8M50.8 223.5h3.8M66 226.1h2.6M66 223.5h2.6M68.9 225.3l.7-.3v2.1a1.02 1.02 0 0 1-.9-.7 1.02 1.02 0 0 1 .2-1.1zM68.9 222.8l.7-.3v2a1.02 1.02 0 0 1-.9-.6 1.02 1.02 0 0 1 .2-1.1zM70.1 225a1.02 1.02 0 0 1 1 1.1 1.02 1.02 0 0 1-1 1zM70.1 222.5a1.02 1.02 0 0 1 1 1 1.02 1.02 0 0 1-1 1zM71.1 223.5h2.6M127 223.5v2.6M129.4 222.8h.3v.7h-.3zM129.5 231.1v1.3h1.3l-1.3 1.3-1.2-1.3h1.2"/>
<path d="M129.5 223.5v2.6M158.7 236.2v5.1M166.1 235.2h.5v1h-.5zM166.4 236.2v6.4h1.2l-1.2 1.2-1.3-1.2h1.3M175.5 233.4h1v.5h-1zM175.5 230.9h1v.5h-1zM175.5 223.3h1v.5h-1zM175.5 220.7h1v.5h-1zM176.5 221h5.1M176.5 223.5h5.1M176.5 231.1h5.1M176.5 233.7h5.1"/>
<path d="M10 260h2M300 253h108v32h-108zM408 260h2M300 278.5h108M300 274.5h108M300 268.5h108M305.5 273.2v.2M305.5 272.5v.1M307.7 270.5v.2M307.7 269.8v.1M310.6 269.1l-1.3 1.9M320 278.5v3"/>
<path d="M330.7 273.5h1.1M332.7 272.5l-.4-.1-.2 .2 .1 .2 .5 .2v.3h-.6M334 272.5l-.4-.1-.3 .3v.4l.1 .2h.6M334.7 272.5l.2-.1 .3 .1 .1 .9M334.7 271.9v1.5M384 278.5v6.5M60 285v2M110 285v2M160 285v2M210 285v2M260 285v2M300 281.5h108"/>
<path d="M310 285v2M360 285v2M393.3 283.6h.9M393.3 282.5l.4-.4v1.5"/>
</g>
<g fill="#840000" stroke="#840000" stroke-width=".18">
<path d="M68.9 215.2l.7-.3v2a1.02 1.02 0 0 1-.9-.6 1.02 1.02 0 0 1 .2-1.1z"/>
<path d="M70.1 214.9a1.02 1.02 0 0 1 1 1 1.02 1.02 0 0 1-1 1z"/>
<path d="M220.3 201.5a1.02 1.02 0 0 1 1.1-.2 1.02 1.02 0 0 1 .6 .9h-2z"/>
<path d="M220 202.7h2v1h-2z"/>
<path d="M220 204.2h2a1.02 1.02 0 0 1-1 1 1.02 1.02 0 0 1-1-1z"/>
<path d="M267.5 61.7h1v1h-1z"/>
<path d="M267 61.5l.7-.3v2a1.02 1.02 0 0 1-.9-.6 1.02 1.02 0 0 1 .2-1.1z"/>
<path d="M268.2 61.2a1.02 1.02 0 0 1 1 1 1.02 1.02 0 0 1-1 1z"/>
<path d="M267.5 64.3h1v1h-1z"/>
<path d="M267 64l.7-.2v2a1.02 1.02 0 0 1-.9-.7 1.02 1.02 0 0 1 .2-1.1z"/>
<path d="M268.2 63.8a1.02 1.02 0 0 1 1 1 1.02 1.02 0 0 1-1 1z"/>
<path d="M267.5 69.3h1v1.1h-1z"/>
<path d="M267 69.1l.7-.3v2.1a1.02 1.02 0 0 1-.9-.7 1.02 1.02 0 0 1 .2-1.1z"/>
<path d="M268.2 68.8a1.02 1.02 0 0 1 1 1.1 1.02 1.02 0 0 1-1 1z"/>
<path d="M267.5 103.6h1v1h-1z"/>
<path d="M267 103.4l.7-.3v2.1a1.02 1.02 0 0 1-.9-.7 1.02 1.02 0 0 1 .2-1.1z"/>
<path d="M268.2 103.1a1.02 1.02 0 0 1 1 1 1.02 1.02 0 0 1-1 1.1z"/>
<path d="M267.5 108.7h1v1h-1z"/>
<path d="M267 108.5l.7-.3v2a1.02 1.02 0 0 1-.9-.6 1.02 1.02 0 0 1 .2-1.1z"/>
<path d="M268.2 108.2a1.02 1.02 0 0 1 1 1 1.02 1.02 0 0 1-1 1z"/>
<path d="M267.5 106.2h1v1h-1z"/>
<path d="M267 105.9l.7-.2v2a1.02 1.02 0 0 1-.9-.7 1.02 1.02 0 0 1 .2-1.1z"/>
<path d="M268.2 105.7a1.02 1.02 0 0 1 1 1 1.02 1.02 0 0 1-1 1z"/>
<path d="M267.5 101.1h1v1h-1z"/>
<path d="M267 100.9l.7-.3v2a1.02 1.02 0 0 1-.9-.6 1.02 1.02 0 0 1 .2-1.1z"/>
<path d="M268.2 100.6a1.02 1.02 0 0 1 1 1 1.02 1.02 0 0 1-1 1z"/>
<path d="M308.9 96.3h2a1.02 1.02 0 0 1-1 1 1.02 1.02 0 0 1-1-1z"/>
<path d="M308.9 94.7h2v1.1h-2z"/>
<path d="M309.2 93.5a1.01 1.01 0 0 1 1.1-.2 1.01 1.01 0 0 1 .6 .9h-2z"/>
<path d="M68.9 225.3l.7-.3v2.1a1.02 1.02 0 0 1-.9-.7 1.02 1.02 0 0 1 .2-1.1z"/>
<path d="M70.1 225a1.02 1.02 0 0 1 1 1.1 1.02 1.02 0 0 1-1 1z"/>
<path d="M155.7 107.4h1v1.1h-1z"/>
<path d="M155.3 107.2l.7-.3v2.1a1.02 1.02 0 0 1-1-.7 1.02 1.02 0 0 1 .3-1.1z"/>
<path d="M156.5 106.9a1.02 1.02 0 0 1 1 1.1 1.02 1.02 0 0 1-1 1z"/>
<path d="M68.9 222.8l.7-.3v2a1.02 1.02 0 0 1-.9-.6 1.02 1.02 0 0 1 .2-1.1z"/>
<path d="M70.1 222.5a1.02 1.02 0 0 1 1 1 1.02 1.02 0 0 1-1 1z"/>
<path d="M331.7 96.3h2.1a1.02 1.02 0 0 1-1.1 1 1.02 1.02 0 0 1-1-1z"/>
<path d="M331.7 94.7h2.1v1.1h-2.1z"/>
<path d="M332 93.5a1.01 1.01 0 0 1 1.1-.2 1.01 1.01 0 0 1 .7 .9h-2.1z"/>
<path d="M125.2 210.6h2.8v.5h-2.8z"/>
<path d="M125.2 193.8h1v1h-1z"/>
<path d="M124.8 193.6l.7-.3v2a1.02 1.02 0 0 1-1-.6 1.02 1.02 0 0 1 .3-1.1z"/>
<path d="M126 193.3a1.02 1.02 0 0 1 1 1 1.02 1.02 0 0 1-1 1z"/>
<path d="M229.4 207.3h1v.5h-1z"/>
<path d="M229.2 206.5a1.02 1.02 0 0 1 1.1-.2 1.02 1.02 0 0 1 .6 1h-2z"/>
<path d="M228.9 207.8h2v1h-2z"/>
<path d="M228.9 209.3h2a1.02 1.02 0 0 1-1 1 1.02 1.02 0 0 1-1-1z"/>
<circle cx="166.4" cy="224.3" r="1.27"/>
<circle cx="166.4" cy="173.5" r="1.27"/>
</g>
<g fill="#ffffc2" stroke="#ffffc2" stroke-width=".18">
<path d="M45.7 214.6h5.1v12.7h-5.1z"/>
<path d="M119.4 49.5h7.6v2.6h-7.6z"/>
<path d="M88.9 49.5h22.9v2.6h-22.9z"/>
<path d="M27.9 113h5.1v2.6h-5.1z"/>
<path d="M25.4 61h2.5v15.2h-2.5z"/>
<path d="M25.4 82.6h2.5v7.6h-2.5z"/>
<path d="M76.2 114.3h25.4v2.5h-25.4z"/>
<path d="M233.7 47h20.3v25.4h-20.3z"/>
<path d="M233.7 86.4h20.3v25.4h-20.3z"/>
<path d="M372.1 111.8h2.5v5h-2.5z"/>
<path d="M368.3 88.9h5.1v12.7h-5.1z"/>
<path d="M53.3 49.5h25.4v2.6h-25.4z"/>
<path d="M124.5 208.3h10.1v15.2h-10.1z"/>
<path d="M156.2 200.7h20.3v35.5h-20.3z"/>
<path d="M214.6 154.9h12.7v12.7h-12.7z"/>
<path d="M66 105.4h2.6v10.2h-2.6z"/>
<path d="M166.4 49.5h15.2v22.9h-15.2z"/>
<path d="M166.4 77.5h15.2v22.8h-15.2z"/>
<path d="M156.2 149.9h20.3v35.5h-20.3z"/>
</g>
<g fill="none" stroke="#840000" stroke-width=".25">
<path d="M53.3 49.5h25.4v2.6h-25.4zM88.9 49.5h22.9v2.6h-22.9zM119.4 49.5h7.6v2.6h-7.6zM166.4 49.5h15.2v22.9h-15.2zM233.7 47h20.3v25.4h-20.3zM25.4 61h2.5v15.2h-2.5zM166.4 77.5h15.2v22.8h-15.2zM25.4 82.6h2.5v7.6h-2.5zM233.7 86.4h20.3v25.4h-20.3zM368.3 88.9h5.1v12.7h-5.1zM27.9 113h5.1v2.6h-5.1zM66 105.4h2.6v10.2h-2.6z"/>
<path d="M76.2 114.3h25.4v2.5h-25.4zM372.1 111.8h2.5v5h-2.5zM49.5 133.4l2.6 1.2-2.6 1.3zM51.4 134v-.6h.7v2.5h.6v-.6M49.5 142.2l2.6 1.3-2.6 1.3zM51.4 142.9v-.7h.7v2.6h.6v-.7M156.2 149.9h20.3v35.5h-20.3zM199.6 146.1h2.1v5h-2.1zM208.5 146.1h2.1v5h-2.1zM158.7 171.5a.64 .64 0 0 0 .7 .6 .64 .64 0 0 0 .6-.6M158.7 163.8a.64 .64 0 0 1 .7-.6 .64 .64 0 0 1 .6 .6M203.2 171.7h5.1v2h-5.1z"/>
<path d="M231.4 174h2v5.1h-2zM239 174h2v5.1h-2zM45.7 214.6h5.1v12.7h-5.1zM124.5 208.3h10.1v15.2h-10.1zM127 213.7h.6l.7 1.3h1.2M127.6 213.7h2.6M128.9 212.5h-.6l-1.3 1.2h-.6M156.2 200.7h20.3v35.5h-20.3zM158.7 214.6a.64 .64 0 0 1 .7-.6 .64 .64 0 0 1 .6 .6M194.3 220h5.1v2h-5.1zM194.3 217.4h5.1v2.1h-5.1zM194.3 209.8h5.1v2h-5.1z"/>
<path d="M194.3 207.3h5.1v2h-5.1zM158.7 222.2a.64 .64 0 0 0 .7 .7 .64 .64 0 0 0 .6-.7"/>
</g>
<g fill="none" stroke="#006464" stroke-width=".18">
<path d="M70.8 46.2l-.3 .9h.7M71.1 46.7v.9M104.8 46.3h.6M104.8 46.8h.4l.3 .2-.2 .5h-.5M129.2 46.3h.8l-.5 .5 .4 .1v.5l-.2 .2-.5-.2M304.3 57.7h.6M329.7 57.7h.6M34.9 78h.7M34.9 77.1l.4-.3v1.2M196.4 62h-.3l-.3 .2 .1 .5h.5M196.4 61.5v1.3M252.4 67.9h.7"/>
<path d="M252.4 62.8h.7M263.2 74.2l-.3 1.3-.2-.9M265.5 61.5h.7M36.6 90.9l.2-.2a.68 .68 0 0 1 .5 .7 .68 .68 0 0 1-.5 .6l-.3-.5zM196.4 90l-.3-.1-.3 .2 .1 .6h.5M196.4 89.5v1.2M375.6 86.3h.7l.1-.2-.1-.3-.7-.1v1.2M45.7 114.8l-.3 .9h.8M46 115.3v.8M68.3 116.1h.8l-.5 .5 .4 .2v.5l-.2 .1h-.5M96.5 118.8l.4-.1 .3 .4-.8 .9h.8M252.4 107.3h.7"/>
<path d="M252.4 102.2h.7M263.2 113.6l-.3 1.3-.2-.9M387.3 114.8l-.3 .9h.8M387.6 115.3v.8M51.4 130.2l.4-.1 .2 .3a.84 .84 0 0 1-.3 1h-.3M51.4 139.1l.4-.1 .2 .3a.84 .84 0 0 1-.3 1h-.3M52 130.7l-.2 .2-.4-.1M52 139.6l-.2 .2-.4-.1M224.4 152.3l.1 .1-.1 .5M174.1 165.2h1M174.1 167.7h1M217.3 162.7h1"/>
<path d="M220.5 178.4h.6M245.4 175.8h.7M191.4 188.4v.1M192.1 187.4l.2-.1a.68 .68 0 0 1 .4 .6 .68 .68 0 0 1-.4 .6l-.3-.4zM57.2 211.8l.3 .1 .1 .2-.6 .1M57.5 212.6l-.3 .1M58.1 211.9l.2-.1 .3 .1 .1 .8M58.1 211.8v.9M126.3 216.8h1.3M126.8 216.8l-.1 .4M127.5 216.8l.1 .4M132.2 218.5h1"/>
<path d="M174.1 218.5h1M174.1 216h1M191.4 239.2v.1M192.1 238.2l.2-.1a.68 .68 0 0 1 .4 .6 .68 .68 0 0 1-.4 .6l-.3-.4z"/>
</g>
<g fill="none" stroke="#840000" stroke-width=".51">
<path d="M293.9 57.9h4M293.9 56.4h4M319.3 57.9h4M319.3 56.4h4M158 162.5a1.9 1.9 0 0 1 2.1-.4 1.9 1.9 0 0 1 1.2 1.7v7.7a1.91 1.91 0 0 1-1.9 1.8 1.91 1.91 0 0 1-1.9-1.8v-7.8l.2-.7zM163.8 167.1v1.3l2.6 2.5M166.4 163.3v10.2M168.9 165.9v1.2l-2.5 2.6M210.1 178.6h4M210.1 177h4M158 213.3a1.9 1.9 0 0 1 2.1-.4 1.9 1.9 0 0 1 1.2 1.7v7.6a1.91 1.91 0 0 1-1.9 1.9 1.91 1.91 0 0 1-1.9-1.9v-7.7l.2-.7zM163.8 217.9v1.3l2.6 2.5"/>
<path d="M166.4 214.1v10.2M168.9 216.7v1.2l-2.5 2.6"/>
</g>
<path d="M255.5 66.9h.7M255.5 106.3h.7" fill="none" stroke="#a90000" stroke-width=".18"/>
<g fill="#840000" stroke="#840000" stroke-width=".25">
<path d="M130.2 213.1l1.2 .6-1.2 .7z"/>
<path d="M129 214.6h.8v.8h-.8z"/>
<path d="M158.7 222.2h1.3a.64 .64 0 0 1-.6 .7 .64 .64 0 0 1-.7-.7z"/>
<path d="M158.7 214.6h1.3v7.6h-1.3z"/>
<path d="M158.9 214.2a.64 .64 0 0 1 .7-.2 .64 .64 0 0 1 .4 .6h-1.3z"/>
<path d="M166.4 211.6l1.2 2.5h-2.5z"/>
<path d="M168.3 215.4h1.2v1.3h-1.2z"/>
<path d="M158.7 171.5h1.3a.64 .64 0 0 1-.6 .6 .64 .64 0 0 1-.7-.6z"/>
<path d="M158.7 163.8h1.3v7.7h-1.3z"/>
<path d="M158.9 163.4a.64 .64 0 0 1 .7-.2 .64 .64 0 0 1 .4 .6h-1.3z"/>
<path d="M166.4 160.8l1.2 2.5h-2.5z"/>
<path d="M168.3 164.6h1.2v1.3h-1.2z"/>
<circle cx="125.7" cy="213.7" r=".63"/>
<circle cx="128.9" cy="212.5" r=".38"/>
<circle cx="163.8" cy="217.3" r=".63"/>
<circle cx="163.8" cy="166.5" r=".63"/>
</g>
<g fill="none" stroke="#0f0f0f" stroke-width=".18">
<path d="M58.8 59v1M61.3 59v1M63.9 59v1M66.4 59v1M68.9 59v1M71.5 59v1M74 59v1M76.6 59v1M89.3 59v1M91.8 59v1M94.3 59v1M96.9 59v1"/>
<path d="M99.4 59v1M102 59v1M104.5 59v1M107 59v1M162.3 53.7h1M162.3 56.2h1M162.3 58.8h1M162.3 51.2h1M228.9 55.6v.8M228.9 56v.1M122.8 64.4v.8l-.8-.7-.3-.1-.1 .1M124.5 64.9l-.5-.5v.8"/>
<path d="M124.6 64.5h.6M162.3 63.9h1M162.3 68.9h1M162.3 79.1h1M162.3 66.4h1M162.3 61.3h1M228.2 63.1h.8l-.5 1.2M228.9 68.8v.5M228.9 60.7v.3M228.9 61.2v.5M162.3 91.8h1M162.3 96.9h1"/>
<path d="M162.3 89.3h1M162.3 94.3h1M162.3 86.7h1M162.3 84.2h1M162.3 81.6h1M77 105v.7M79.6 105.1v.8l-.7-.8h-.3l-.2 .1M81.3 105.5l-.4-.4v.8M81.5 105.1h.5M86.5 105.1h.6M89.1 105.1h.5M92.3 105.6l-1.3-.6v.9"/>
<path d="M93.7 105.1h.3M94.2 105.1h.5M96.2 105.1h.9M96.6 105.1h.2M228.2 105h.7l-.4 .5M228.2 102.4h.7l-.4 .5M228.8 107.6l.1 .2v.3l-.7 .7h.7M228.9 100.5v.6M228.9 103.1v.5M228.9 105.6v.5M361.6 115.1h.7M362.2 111.4l.1 .2-.1 .3-.7 .7h.8"/>
</g>
<path d="M21.6 40.6h110.5v81.3h-110.5zM144.8 40.6h55.9v80.1h-55.9zM221 40.6h170.2v80.1h-170.2zM115.6 134.6h138.4v114.3h-138.4z" fill="none" stroke="#0000c2" stroke-width=".18"/>
<g fill="none" stroke="#009600" stroke-width=".18">
<path d="M54.6 55.9v14M57.1 55.9v14M59.7 55.9v14M62.2 55.9v14M64.8 55.9v14M67.3 55.9v14M69.8 55.9v14M72.4 55.9v14M74.9 55.9v14M77.5 55.9v14M90.2 55.9v14M92.7 55.9v14"/>
<path d="M95.2 55.9v14M97.8 55.9v14M100.3 55.9v14M102.9 55.9v14M105.4 55.9v14M107.9 55.9v14M110.5 55.9v14M120.6 55.9v14M123.2 55.9v14M125.7 55.9v14M152.4 57.2h11.4M152.4 59.7h11.4"/>
<path d="M152.4 54.6h11.4M152.4 52.1h11.4M223.5 49.5h7.6v2.6M223.5 57.2h7.6M223.5 54.6h7.6M233.7 44.5h7.6M246.4 44.5h7.6M295.9 53.3h10.2M321.3 53.3h7.6M31.7 69.9h11.5M31.7 64.8h11.5M31.7 62.2h11.5"/>
<path d="M31.7 67.3h11.5M31.7 74.9h11.5M31.7 72.4h11.5M152.4 69.9h11.4M152.4 64.8h11.4M152.4 62.2h11.4M152.4 67.3h11.4M152.4 74.9h21.6M223.5 69.9h7.6M223.5 64.8h7.6M223.5 62.2h7.6M256.5 69.9h7.7"/>
<path d="M256.5 64.8h7.7M256.5 62.2h7.7M271.8 69.9h7.6M271.8 64.8h7.6M271.8 62.2h7.6M29.2 97.8v11.4M31.7 88.9h11.5M31.7 83.8h11.5M31.7 86.4h11.5M31.7 97.8v11.4M77.5 99.1v11.4M80 99.1v11.4"/>
<path d="M82.5 99.1v11.4M85.1 99.1v11.4M87.6 99.1v11.4M90.2 99.1v11.4M92.7 99.1v11.4M95.2 99.1v11.4M97.8 99.1v11.4M100.3 99.1v11.4M152.4 92.7h11.4M152.4 97.8h11.4M152.4 95.3h11.4M152.4 90.2h11.4"/>
<path d="M152.4 80h11.4M152.4 82.6h11.4M152.4 85.1h11.4M152.4 87.6h11.4M223.5 88.9h7.6v2.5M223.5 96.5h7.6M223.5 94h7.6M233.7 83.8h7.6M246.4 83.8h7.6M309.9 90.2h11.4M313.7 95.3h7.6M332.7 90.2h11.5"/>
<path d="M336.5 95.3h7.7M356.9 92.7h7.6M356.9 97.8h7.6M356.9 95.3h7.6M356.9 90.2h7.6M377.2 92.7h7.6M377.2 97.8h7.6M377.2 95.3h7.6M377.2 90.2h7.6M50.8 109.2h11.4M50.8 106.7h11.4M50.8 114.3h11.4"/>
<path d="M50.8 111.8h11.4M174 102.9h-21.6v5.1M223.5 101.6h7.6M223.5 104.1h7.6M223.5 109.2h7.6M223.5 106.7h7.6M256.5 101.6h7.7M256.5 104.1h7.7M256.5 109.2h7.7M256.5 106.7h7.7M271.8 101.6h7.6M271.8 104.1h7.6"/>
<path d="M271.8 109.2h7.6M271.8 106.7h7.6M309.9 100.3h11.4M332.7 100.3h11.5M356.9 115.6h11.4M356.9 100.3h7.6M356.9 113h11.4M377.2 100.3h7.6M47 134.6h-11.4v8.9h11.4M54.6 134.6h11.4v8.9h-11.4M181.6 157.5h30.5M181.6 152.4h15.2v20.3h5.1"/>
<path d="M200.7 152.4v5.1M209.5 152.4v7.6M229.9 157.5h12.7v12.7h-61v2.5M181.6 160h30.5M209.5 172.7h2.6M212.1 162.6h-22.9v5h-7.6v-2.5M212.1 165.1v8.9M229.9 162.6h10.1v10.1M229.9 165.1h2.5v7.6M229.9 160h3.8M152.4 190.5v50.8h6.3M158.7 190.5h-36.8v35.6h5.1"/>
<path d="M181.6 180.3v10.2h-15.2M221 198.1h16.5M30.5 215.9h11.4M30.5 218.4h11.4M54.6 215.9h11.4M54.6 218.4h11.4M73.7 215.9h11.4M137.2 215.9h11.4M137.2 218.4h11.4M137.2 210.8h11.4M181.6 215.9v2.5h11.4M181.6 210.8h11.4"/>
<path d="M181.6 208.3h11.4M181.6 203.2h35.6M200.7 218.4h15.2M200.7 210.8h3.8M200.7 208.3h3.8M221 208.3h5.1M229.9 213.4h17.7M229.9 203.2h17.7M30.5 221h11.4M30.5 226.1h11.4M54.6 221h11.4M54.6 226.1h11.4"/>
<path d="M54.6 223.5h11.4M73.7 226.1h11.4M73.7 223.5h11.4M129.5 226.1v5M181.6 231.1v10.2h-15.2M193 221h-11.4v2.5M200.7 221h15.2"/>
</g>
<path d="M230.5 66.7l1.2 1.2M231.7 66.7l-1.2 1.2M255.9 66.7l1.2 1.2M257.1 66.7l-1.2 1.2M41.3 222.9l1.2 1.2M42.5 222.9l-1.2 1.2" fill="none" stroke="#000084" stroke-width=".18"/>
<g fill="#009600" stroke="#009600" stroke-width=".18">
<circle cx="231.1" cy="88.9" r=".46"/>
<circle cx="231.1" cy="49.5" r=".46"/>
<circle cx="209.5" cy="160" r=".46"/>
<circle cx="212.1" cy="172.7" r=".46"/>
<circle cx="181.6" cy="167.6" r=".46"/>
<circle cx="121.9" cy="194.3" r=".46"/>
<circle cx="152.4" cy="190.5" r=".46"/>
<circle cx="181.6" cy="233.7" r=".46"/>
<circle cx="166.4" cy="241.3" r=".46"/>
<circle cx="181.6" cy="221" r=".46"/>
<circle cx="181.6" cy="218.4" r=".46"/>
<circle cx="181.6" cy="170.2" r=".46"/>
<circle cx="166.4" cy="190.5" r=".46"/>
<circle cx="181.6" cy="182.9" r=".46"/>
<circle cx="200.7" cy="157.5" r=".46"/>
</g>
<use href="#words"/>
</svg>
